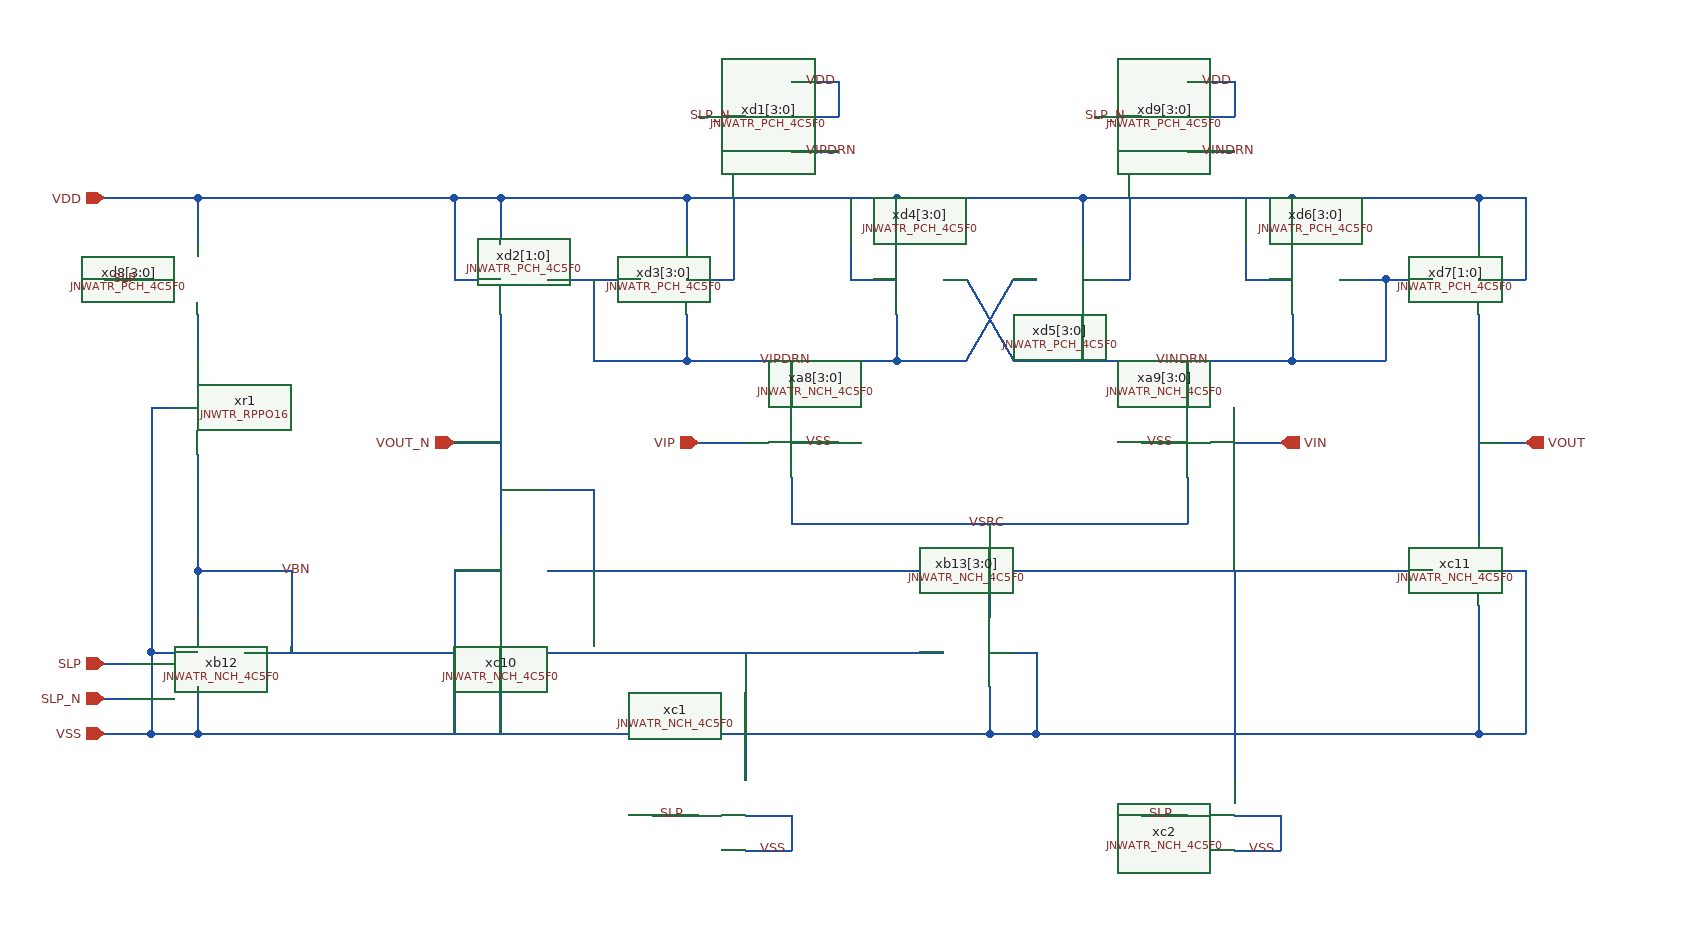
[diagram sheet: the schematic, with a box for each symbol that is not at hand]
v {xschem version=3.4.6 file_version=1.2}
G {}
K {}
V {}
S {}
E {}
N 480 300 520 300 {lab=VDD}
N 480 760 520 760 {lab=VSS}
N 1660 510 1700 510 {lab=VOUT}
N 560 520 560 620 {lab=VBIAS}
N 520 480 540 480 {lab=VSS}
N 520 300 560 300 {lab=VDD}
N 560 300 560 340 {lab=VDD}
N 520 690 560 690 {lab=VSS}
N 560 720 560 760 {lab=VSS}
N 520 760 560 760 {lab=VSS}
N 600 690 1200 690 {lab=VBIAS}
N 560 760 1240 760 {lab=VSS}
N 1240 720 1240 760 {lab=VSS}
N 1070 540 1070 580 {lab=VSRC}
N 1070 580 1410 580 {lab=VSRC}
N 1410 540 1410 580 {lab=VSRC}
N 1240 580 1240 660 {lab=VSRC}
N 1070 510 1110 510 {lab=VSS}
N 1370 510 1410 510 {lab=VSS}
N 1240 690 1280 690 {lab=VSS}
N 1280 690 1280 760 {lab=VSS}
N 1240 760 1280 760 {lab=VSS}
N 1160 400 1160 440 {lab=VIPDRN}
N 1410 440 1410 480 {lab=VINDRN}
N 1450 510 1490 510 {lab=VIN}
N 990 510 1030 510 {lab=VIP}
N 1220 370 1260 440 {lab=VINDRN}
N 1320 370 1360 370 {lab=VDD}
N 1360 300 1360 370 {lab=VDD}
N 980 370 1020 370 {lab=VDD}
N 1020 300 1020 370 {lab=VDD}
N 1160 300 1160 340 {lab=VDD}
N 1320 300 1320 340 {lab=VDD}
N 520 690 520 760 {lab=VSS}
N 1000 440 1160 440 {lab=VIPDRN}
N 1220 440 1260 370 {lab=VIPDRN}
N 560 620 640 620 {lab=VBIAS}
N 640 620 640 690 {lab=VBIAS}
N 560 620 560 660 {lab=VBIAS}
N 1660 400 1660 590 {lab=VOUT}
N 1660 650 1660 760 {lab=VSS}
N 1280 760 1660 760 {lab=VSS}
N 1660 300 1660 340 {lab=VDD}
N 1660 370 1700 370 {lab=VDD}
N 1700 300 1700 370 {lab=VDD}
N 1660 300 1700 300 {lab=VDD}
N 1660 620 1700 620 {lab=VSS}
N 1700 620 1700 760 {lab=VSS}
N 1660 760 1700 760 {lab=VSS}
N 1200 370 1220 370 {lab=VINDRN}
N 1260 370 1280 370 {lab=VIPDRN}
N 1260 440 1480 440 {lab=VINDRN}
N 860 620 1620 620 {lab=VOUT_N}
N 780 510 820 510 {lab=VOUT_N}
N 820 400 820 590 {lab=VOUT_N}
N 820 650 820 760 {lab=VSS}
N 820 300 820 340 {lab=VDD}
N 780 370 820 370 {lab=VDD}
N 780 300 780 370 {lab=VDD}
N 780 300 820 300 {lab=VDD}
N 780 620 820 620 {lab=VSS}
N 780 620 780 760 {lab=VSS}
N 1070 440 1070 480 {lab=VIPDRN}
N 980 440 1000 440 {lab=VIPDRN}
N 1480 440 1500 440 {lab=VINDRN}
N 1320 400 1320 440 {lab=VINDRN}
N 1500 300 1500 340 {lab=VDD}
N 1500 400 1500 440 {lab=VINDRN}
N 980 400 980 440 {lab=VIPDRN}
N 980 300 980 340 {lab=VDD}
N 900 440 980 440 {lab=VIPDRN}
N 900 370 900 440 {lab=VIPDRN}
N 860 370 940 370 {lab=VIPDRN}
N 1500 440 1580 440 {lab=VINDRN}
N 1580 370 1580 440 {lab=VINDRN}
N 1580 370 1620 370 {lab=VINDRN}
N 1540 370 1580 370 {lab=VINDRN}
N 1160 440 1220 440 {lab=VIPDRN}
N 820 300 980 300 {lab=VDD}
N 980 300 1070 300 {lab=VDD}
N 1070 300 1160 300 {lab=VDD}
N 1160 300 1320 300 {lab=VDD}
N 1320 300 1410 300 {lab=VDD}
N 1410 300 1500 300 {lab=VDD}
N 1500 300 1660 300 {lab=VDD}
N 560 300 780 300 {lab=VDD}
N 1460 370 1500 370 {lab=VDD}
N 1460 300 1460 370 {lab=VDD}
N 1120 370 1160 370 {lab=VDD}
N 1120 300 1120 370 {lab=VDD}
N 900 550 900 620 {lab=VOUT_N}
N 820 550 900 550 {lab=VOUT_N}
N 1070 260 1110 260 {lab=VIPDRN}
N 1070 200 1110 200 {lab=VDD}
N 1070 230 1110 230 {lab=VDD}
N 1110 200 1110 230 {lab=VDD}
N 1030 830 1070 830 {lab=VSS}
N 1070 830 1070 860 {lab=VSS}
N 1030 860 1070 860 {lab=VSS}
N 1030 690 1030 800 {lab=VBIAS}
N 950 830 990 830 {lab=SLP}
N 990 230 1030 230 {lab=SLP_N}
N 520 480 520 690 {lab=VSS}
N 560 400 560 440 {lab=#net1}
N 480 370 520 370 {lab=SLP}
N 1410 260 1450 260 {lab=VINDRN}
N 1410 200 1450 200 {lab=VDD}
N 1410 230 1450 230 {lab=VDD}
N 1450 200 1450 230 {lab=VDD}
N 1330 230 1370 230 {lab=SLP_N}
N 1450 830 1490 830 {lab=VSS}
N 1490 830 1490 860 {lab=VSS}
N 1450 860 1490 860 {lab=VSS}
N 1370 830 1410 830 {lab=SLP}
N 1450 620 1450 800 {lab=VOUT_N}
N 480 700 500 700 {lab=SLP}
N 480 730 500 730 {lab=SLP_N}
C {devices/ipin.sym} 480 300 0 0 {name=p3 lab=VDD}
C {devices/ipin.sym} 480 760 0 0 {name=p4 lab=VSS}
C {devices/opin.sym} 1700 510 0 0 {name=p5 lab=VOUT
}
C {JNW_TR_SKY130A/JNWTR_RPPO16.sym} 560 520 1 1 {name=xr1}
C {JNW_ATR_SKY130A/JNWATR_NCH_4C5F0.sym} 1450 510 0 1 {name=xa9[3:0]}
C {JNW_ATR_SKY130A/JNWATR_NCH_4C5F0.sym} 1200 690 0 0 {name=xb13[3:0]}
C {JNW_ATR_SKY130A/JNWATR_NCH_4C5F0.sym} 1030 510 0 0 {name=xa8[3:0]}
C {JNW_ATR_SKY130A/JNWATR_NCH_4C5F0.sym} 600 690 0 1 {name=xb12}
C {devices/ipin.sym} 1490 510 0 1 {name=p1 lab=VIN}
C {devices/ipin.sym} 990 510 0 0 {name=p2 lab=VIP}
C {JNW_ATR_SKY130A/JNWATR_PCH_4C5F0.sym} 1200 370 0 1 {name=xd4[3:0]}
C {JNW_ATR_SKY130A/JNWATR_PCH_4C5F0.sym} 1280 370 0 0 {name=xd5[3:0]}
C {JNW_ATR_SKY130A/JNWATR_PCH_4C5F0.sym} 1540 370 0 1 {name=xd6[3:0]}
C {JNW_ATR_SKY130A/JNWATR_NCH_4C5F0.sym} 1620 620 0 0 {name=xc11}
C {devices/opin.sym} 780 510 0 1 {name=p6 lab=VOUT_N
}
C {JNW_ATR_SKY130A/JNWATR_PCH_4C5F0.sym} 860 370 0 1 {name=xd2[1:0]}
C {JNW_ATR_SKY130A/JNWATR_NCH_4C5F0.sym} 860 620 0 1 {name=xc10}
C {JNW_ATR_SKY130A/JNWATR_PCH_4C5F0.sym} 940 370 0 0 {name=xd3[3:0]}
C {JNW_ATR_SKY130A/JNWATR_PCH_4C5F0.sym} 1620 370 0 0 {name=xd7[1:0]}
C {devices/lab_wire.sym} 630 620 0 1 {name=p7 sig_type=std_logic lab=VBN}
C {devices/lab_wire.sym} 1220 580 0 1 {name=p8 sig_type=std_logic lab=VSRC}
C {devices/lab_wire.sym} 1040 440 0 1 {name=p9 sig_type=std_logic lab=VIPDRN}
C {devices/lab_wire.sym} 1380 440 0 1 {name=p10 sig_type=std_logic lab=VINDRN}
C {devices/lab_wire.sym} 1080 510 2 0 {name=p11 sig_type=std_logic lab=VSS}
C {devices/lab_wire.sym} 1400 510 2 1 {name=p12 sig_type=std_logic lab=VSS}
C {JNW_ATR_SKY130A/JNWATR_NCH_4C5F0.sym} 990 830 0 0 {name=xc1}
C {JNW_ATR_SKY130A/JNWATR_PCH_4C5F0.sym} 1030 230 0 0 {name=xd1[3:0]}
C {devices/lab_wire.sym} 1040 860 2 0 {name=p14 sig_type=std_logic lab=VSS}
C {devices/lab_wire.sym} 980 830 0 0 {name=p15 sig_type=std_logic lab=SLP}
C {JNW_ATR_SKY130A/JNWATR_PCH_4C5F0.sym} 520 370 0 0 {name=xd8[3:0]}
C {devices/lab_wire.sym} 510 370 0 0 {name=p16 sig_type=std_logic lab=SLP}
C {devices/lab_wire.sym} 1020 230 0 0 {name=p17 sig_type=std_logic lab=SLP_N}
C {devices/lab_wire.sym} 1080 200 0 1 {name=p18 sig_type=std_logic lab=VDD}
C {devices/lab_wire.sym} 1080 260 2 0 {name=p19 sig_type=std_logic lab=VIPDRN}
C {JNW_ATR_SKY130A/JNWATR_PCH_4C5F0.sym} 1370 230 0 0 {name=xd9[3:0]}
C {devices/lab_wire.sym} 1360 230 0 0 {name=p20 sig_type=std_logic lab=SLP_N}
C {devices/lab_wire.sym} 1420 200 0 1 {name=p21 sig_type=std_logic lab=VDD}
C {devices/lab_wire.sym} 1420 260 2 0 {name=p22 sig_type=std_logic lab=VINDRN}
C {JNW_ATR_SKY130A/JNWATR_NCH_4C5F0.sym} 1410 830 0 0 {name=xc2}
C {devices/lab_wire.sym} 1460 860 2 0 {name=p24 sig_type=std_logic lab=VSS}
C {devices/lab_wire.sym} 1400 830 0 0 {name=p25 sig_type=std_logic lab=SLP}
C {devices/ipin.sym} 480 700 0 0 {name=p23 lab=SLP}
C {devices/ipin.sym} 480 730 0 0 {name=p26 lab=SLP_N}
